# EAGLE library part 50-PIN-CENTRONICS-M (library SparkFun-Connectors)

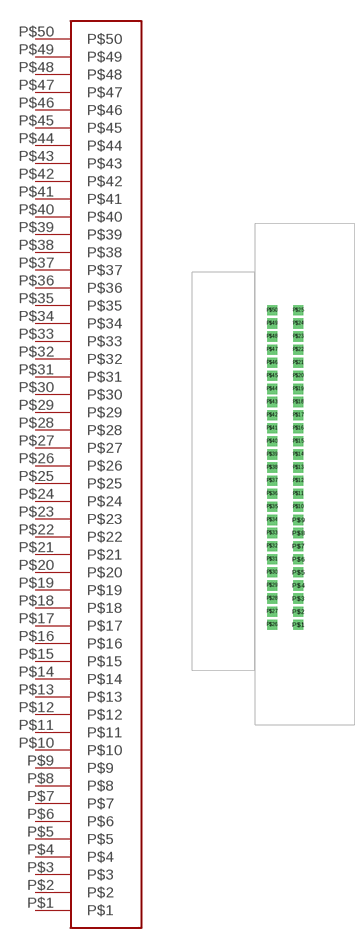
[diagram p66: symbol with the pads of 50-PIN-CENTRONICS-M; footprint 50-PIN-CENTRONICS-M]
Designator prefix -

## 50-PIN-CENTRONICS-MMALE  [50-PIN-CENTRONICS-M]
P$1  P$1
P$2  P$2
P$3  P$3
P$4  P$4
P$5  P$5
P$6  P$6
P$7  P$7
P$8  P$8
P$9  P$9
P$10  P$10
P$11  P$11
P$12  P$12
P$13  P$13
P$14  P$14
P$15  P$15
P$16  P$16
P$17  P$17
P$18  P$18
P$19  P$19
P$20  P$20
P$21  P$21
P$22  P$22
P$23  P$23
P$24  P$24
P$25  P$25
P$26  P$26
P$27  P$27
P$28  P$28
P$29  P$29
P$30  P$30
P$31  P$31
P$32  P$32
P$33  P$33
P$34  P$34
P$35  P$35
P$36  P$36
P$37  P$37
P$38  P$38
P$39  P$39
P$40  P$40
P$41  P$41
P$42  P$42
P$43  P$43
P$44  P$44
P$45  P$45
P$46  P$46
P$47  P$47
P$48  P$48
P$49  P$49
P$50  P$50

## Footprint 50-PIN-CENTRONICS-M (pad centres in mm)
drill 0.9 pad 1.676 square: P$1 4.318,0; P$2 4.318,2.159; P$3 4.318,4.318; P$4 4.318,6.477; P$5 4.318,8.636; P$6 4.318,10.795; P$7 4.318,12.954; P$8 4.318,15.113; P$9 4.318,17.272; P$10 4.318,19.431; P$11 4.318,21.59; P$12 4.318,23.749; P$13 4.318,25.908; P$14 4.318,28.067; P$15 4.318,30.226; P$16 4.318,32.385; P$17 4.318,34.544; P$18 4.318,36.703; P$19 4.318,38.862; P$20 4.318,41.021; P$21 4.318,43.18; P$22 4.318,45.339; P$23 4.318,47.498; P$24 4.318,49.657; P$25 4.318,51.816; P$26 0,0; P$27 0,2.159; P$28 0,4.318; P$29 0,6.477; P$30 0,8.636; P$31 0,10.795; P$32 0,12.954; P$33 0,15.113; P$34 0,17.272; P$35 0,19.431; P$36 0,21.59; P$37 0,23.749; P$38 0,25.908; P$39 0,28.067; P$40 0,30.226; P$41 0,32.385; P$42 0,34.544; P$43 0,36.703; P$44 0,38.862; P$45 0,41.021; P$46 0,43.18; P$47 0,45.339; P$48 0,47.498; P$49 0,49.657; P$50 0,51.816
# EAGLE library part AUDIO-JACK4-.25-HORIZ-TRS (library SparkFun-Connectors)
1/4" TRS jack, horizontal Production SKU: COM-11144 Footprint unproven - datasheet and part seem to be slightly different

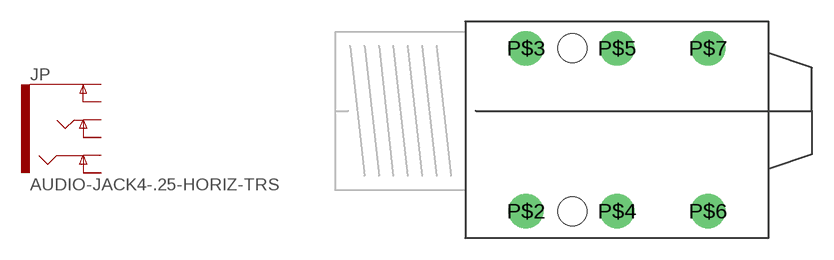
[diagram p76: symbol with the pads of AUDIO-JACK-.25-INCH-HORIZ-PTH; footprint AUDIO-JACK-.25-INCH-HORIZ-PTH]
Designator prefix JP

## AUDIO-JACK4-.25-HORIZ-TRS (PROD_ID: COM-11144)  [AUDIO-JACK-.25-INCH-HORIZ-PTH]
P$2  EARTH
P$3  EARTH-NORM
P$4  RING
P$5  RING-NORM
P$6  TIP
P$7  TIP-NORM

## Footprint AUDIO-JACK-.25-INCH-HORIZ-PTH (pad centres in mm)
drill 1.6: P$2 4.2,-6.92; P$3 4.2,4.38; P$4 10.5,-6.92; P$5 10.5,4.38; P$6 16.8,-6.92; P$7 16.8,4.38
hole 2 at 7.4,4.38
hole 2 at 7.4,-6.92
